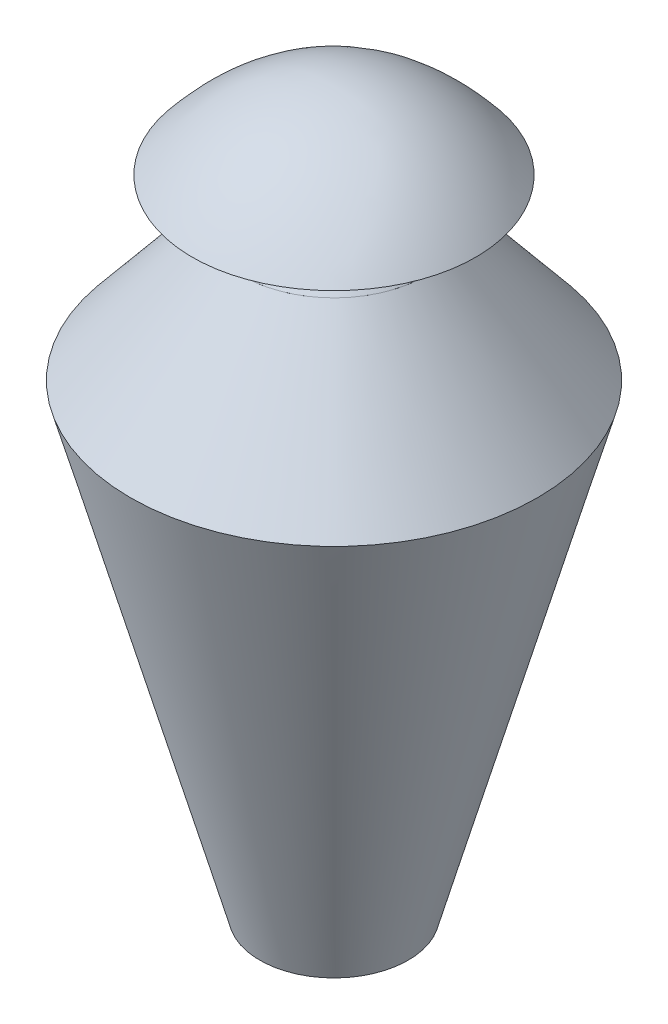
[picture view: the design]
ISO-10303-21;
HEADER;
FILE_DESCRIPTION(('STEP AP214'),'2;1');
FILE_NAME('part.step','',(''),(''),'','','');
FILE_SCHEMA(('AUTOMOTIVE_DESIGN { 1 0 10303 214 1 1 1 1 }'));
ENDSEC;
DATA;
#1=APPLICATION_CONTEXT('core data for automotive mechanical design processes');
#2=APPLICATION_PROTOCOL_DEFINITION('international standard','automotive_design',2000,#1);
#3=PRODUCT_CONTEXT('',#1,'mechanical');
#4=PRODUCT('Part','Part','',(#3));
#5=PRODUCT_RELATED_PRODUCT_CATEGORY('part','',(#4));
#6=PRODUCT_DEFINITION_FORMATION('','',#4);
#7=PRODUCT_DEFINITION_CONTEXT('part definition',#1,'design');
#8=PRODUCT_DEFINITION('design','',#6,#7);
#9=PRODUCT_DEFINITION_SHAPE('','',#8);
#10=(LENGTH_UNIT() NAMED_UNIT(*) SI_UNIT(.MILLI.,.METRE.));
#11=(NAMED_UNIT(*) PLANE_ANGLE_UNIT() SI_UNIT($,.RADIAN.));
#12=(NAMED_UNIT(*) SI_UNIT($,.STERADIAN.) SOLID_ANGLE_UNIT());
#13=UNCERTAINTY_MEASURE_WITH_UNIT(LENGTH_MEASURE(1.E-05),#10,'distance_accuracy_value','');
#14=(GEOMETRIC_REPRESENTATION_CONTEXT(3) GLOBAL_UNCERTAINTY_ASSIGNED_CONTEXT((#13)) GLOBAL_UNIT_ASSIGNED_CONTEXT((#10,
#11,#12)) REPRESENTATION_CONTEXT('',''));
#15=CARTESIAN_POINT('',(0.,0.,0.));
#16=DIRECTION('',(0.,0.,1.));
#17=DIRECTION('',(1.,0.,0.));
#18=AXIS2_PLACEMENT_3D('',#15,#16,#17);
#19=CARTESIAN_POINT('',(-14.2559215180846,82.6136920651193,-14.4318182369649));
#20=CARTESIAN_POINT('',(-8.55355290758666,89.3983986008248,-14.4318182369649));
#21=CARTESIAN_POINT('',(-2.85118429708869,93.0930925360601,-14.4318182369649));
#22=CARTESIAN_POINT('',(2.85118431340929,93.0720125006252,-14.4318182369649));
#23=CARTESIAN_POINT('',(8.55355292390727,89.3990041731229,-14.4318182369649));
#24=CARTESIAN_POINT('',(14.2559215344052,82.6614479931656,-14.4318182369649));
#25=CARTESIAN_POINT('',(-14.2559215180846,89.5757486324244,-8.65516518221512));
#26=CARTESIAN_POINT('',(-8.55355290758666,96.904811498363,-8.65516518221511));
#27=CARTESIAN_POINT('',(-2.85118429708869,100.30232000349,-8.65516518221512));
#28=CARTESIAN_POINT('',(2.85118431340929,100.275838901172,-8.65516518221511));
#29=CARTESIAN_POINT('',(8.55355292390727,96.8840880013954,-8.65516518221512));
#30=CARTESIAN_POINT('',(14.2559215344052,89.5838472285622,-8.65516518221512));
#31=CARTESIAN_POINT('',(-14.2559215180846,93.3592027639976,-2.87851212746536));
#32=CARTESIAN_POINT('',(-8.55355290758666,100.377822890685,-2.87851212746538));
#33=CARTESIAN_POINT('',(-2.85118429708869,103.246310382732,-2.87851212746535));
#34=CARTESIAN_POINT('',(2.85118431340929,103.179594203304,-2.87851212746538));
#35=CARTESIAN_POINT('',(8.55355292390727,100.331467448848,-2.87851212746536));
#36=CARTESIAN_POINT('',(14.2559215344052,93.3337100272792,-2.87851212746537));
#37=CARTESIAN_POINT('',(-14.2559215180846,93.3444529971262,2.89814092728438));
#38=CARTESIAN_POINT('',(-8.55355290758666,100.371031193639,2.89814092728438));
#39=CARTESIAN_POINT('',(-2.85118429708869,103.205456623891,2.89814092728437));
#40=CARTESIAN_POINT('',(2.85118431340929,103.258325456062,2.89814092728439));
#41=CARTESIAN_POINT('',(8.55355292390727,100.40060309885,2.89814092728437));
#42=CARTESIAN_POINT('',(14.2559215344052,93.3631287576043,2.89814092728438));
#43=CARTESIAN_POINT('',(-14.2559215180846,89.5573572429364,8.67479398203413));
#44=CARTESIAN_POINT('',(-8.55355290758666,96.8645126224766,8.67479398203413));
#45=CARTESIAN_POINT('',(-2.85118429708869,100.264019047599,8.67479398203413));
#46=CARTESIAN_POINT('',(2.85118431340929,100.301314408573,8.67479398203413));
#47=CARTESIAN_POINT('',(8.55355292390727,96.8903892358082,8.67479398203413));
#48=CARTESIAN_POINT('',(14.2559215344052,89.5657791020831,8.67479398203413));
#49=CARTESIAN_POINT('',(-14.2559215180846,82.6217733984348,14.4514470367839));
#50=CARTESIAN_POINT('',(-8.55355290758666,89.3882817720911,14.4514470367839));
#51=CARTESIAN_POINT('',(-2.85118429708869,93.0341993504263,14.4514470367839));
#52=CARTESIAN_POINT('',(2.85118431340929,93.0764137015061,14.4514470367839));
#53=CARTESIAN_POINT('',(8.55355292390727,89.3744885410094,14.4514470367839));
#54=CARTESIAN_POINT('',(14.2559215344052,82.5669419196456,14.4514470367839));
#55=B_SPLINE_SURFACE_WITH_KNOTS('',5,5,((#19,#20,#21,#22,#23,#24),(#25,#26,#27,#28,#29,#30),
(#31,#32,#33,#34,#35,#36),(#37,#38,#39,#40,#41,#42),(#43,#44,#45,#46,#47,#48),(#49,#50,#51,#52,
#53,#54)),.UNSPECIFIED.,.F.,.F.,.F.,(6,6),(6,6),(-13.7340018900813,15.1492633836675),
(-14.2559215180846,14.2559215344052),.UNSPECIFIED.);
#56=OFFSET_SURFACE('',#55,10.,.F.);
#57=CARTESIAN_POINT('',(0.000152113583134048,98.2263380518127,-21.67346671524));
#58=CARTESIAN_POINT('',(-0.354370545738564,98.2261840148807,-21.6736080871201));
#59=CARTESIAN_POINT('',(-0.708894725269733,98.2262117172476,-21.6648915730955));
#60=CARTESIAN_POINT('',(-1.41708255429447,98.2265999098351,-21.6298200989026));
#61=CARTESIAN_POINT('',(-1.77074617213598,98.2269604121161,-21.6034644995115));
#62=CARTESIAN_POINT('',(-2.47633651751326,98.2279835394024,-21.5331908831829));
#63=CARTESIAN_POINT('',(-2.82826318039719,98.228646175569,-21.4892722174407));
#64=CARTESIAN_POINT('',(-3.52951266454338,98.2302345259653,-21.3840080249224));
#65=CARTESIAN_POINT('',(-3.87883538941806,98.2311602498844,-21.3226618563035));
#66=CARTESIAN_POINT('',(-4.57401850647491,98.2332265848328,-21.1827248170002));
#67=CARTESIAN_POINT('',(-4.91987880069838,98.2343672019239,-21.1041334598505));
#68=CARTESIAN_POINT('',(-5.60728765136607,98.2368061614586,-20.9299397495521));
#69=CARTESIAN_POINT('',(-5.94883620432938,98.2381045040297,-20.8343373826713));
#70=CARTESIAN_POINT('',(-6.62678251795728,98.2407918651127,-20.6264084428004));
#71=CARTESIAN_POINT('',(-6.96318055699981,98.2421808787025,-20.514082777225));
#72=CARTESIAN_POINT('',(-7.62999662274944,98.2449802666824,-20.273043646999));
#73=CARTESIAN_POINT('',(-7.96041551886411,98.2463906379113,-20.144332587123));
#74=CARTESIAN_POINT('',(-8.61446529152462,98.2491797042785,-19.8708905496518));
#75=CARTESIAN_POINT('',(-8.93809773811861,98.2505584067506,-19.7261633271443));
#76=CARTESIAN_POINT('',(-9.57780759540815,98.2532322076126,-19.421091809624));
#77=CARTESIAN_POINT('',(-9.89388704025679,98.254527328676,-19.2607517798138));
#78=CARTESIAN_POINT('',(-10.5177613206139,98.2569855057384,-18.9248866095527));
#79=CARTESIAN_POINT('',(-10.8255583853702,98.2581485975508,-18.7493656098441));
#80=CARTESIAN_POINT('',(-11.4321706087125,98.2602998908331,-18.3835955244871));
#81=CARTESIAN_POINT('',(-11.7309879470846,98.2612881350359,-18.1933500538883));
#82=CARTESIAN_POINT('',(-12.31896906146,98.26305574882,-17.7986102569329));
#83=CARTESIAN_POINT('',(-12.6081348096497,98.2638351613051,-17.5941188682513));
#84=CARTESIAN_POINT('',(-13.1761594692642,98.2651639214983,-17.1713872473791));
#85=CARTESIAN_POINT('',(-13.4550201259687,98.2657133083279,-16.9531493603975));
#86=CARTESIAN_POINT('',(-14.001795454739,98.2665784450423,-16.5034429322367));
#87=CARTESIAN_POINT('',(-14.2697116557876,98.2668942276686,-16.2719762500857));
#88=CARTESIAN_POINT('',(-14.7940014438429,98.2672699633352,-15.7963633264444));
#89=CARTESIAN_POINT('',(-15.0503759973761,98.2673299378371,-15.5522181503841));
#90=CARTESIAN_POINT('',(-15.5510088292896,98.2671883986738,-15.0518067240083));
#91=CARTESIAN_POINT('',(-15.7952671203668,98.2669868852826,-14.7955404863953));
#92=CARTESIAN_POINT('',(-16.2711137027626,98.2663272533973,-14.2714596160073));
#93=CARTESIAN_POINT('',(-16.5027008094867,98.2658691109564,-14.0036439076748));
#94=CARTESIAN_POINT('',(-16.9526689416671,98.2647087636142,-13.4570563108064));
#95=CARTESIAN_POINT('',(-17.1710475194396,98.2640065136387,-13.1782824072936));
#96=CARTESIAN_POINT('',(-17.594078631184,98.2623758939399,-12.6103967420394));
#97=CARTESIAN_POINT('',(-17.7987276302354,98.2614474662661,-12.321282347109));
#98=CARTESIAN_POINT('',(-18.1937966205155,98.2593864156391,-11.7333656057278));
#99=CARTESIAN_POINT('',(-18.3842123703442,98.2582537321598,-11.4345604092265));
#100=CARTESIAN_POINT('',(-18.7503333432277,98.2558083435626,-10.8279463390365));
#101=CARTESIAN_POINT('',(-18.9260340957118,98.2544955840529,-10.5201347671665));
#102=CARTESIAN_POINT('',(-19.2622613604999,98.2517387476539,-9.89620298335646));
#103=CARTESIAN_POINT('',(-19.4227829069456,98.2502946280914,-9.58008009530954));
#104=CARTESIAN_POINT('',(-19.7282134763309,98.24732347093,-8.94026268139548));
#105=CARTESIAN_POINT('',(-19.8731177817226,98.2457964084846,-8.61656590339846));
#106=CARTESIAN_POINT('',(-20.1469027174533,98.2427117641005,-7.96238046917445));
#107=CARTESIAN_POINT('',(-20.2757797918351,98.2411541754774,-7.6318903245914));
#108=CARTESIAN_POINT('',(-20.5171332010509,98.2380678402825,-6.96493099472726));
#109=CARTESIAN_POINT('',(-20.629607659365,98.236539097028,-6.62846113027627));
#110=CARTESIAN_POINT('',(-20.8378199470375,98.2335767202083,-5.95037582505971));
#111=CARTESIAN_POINT('',(-20.9335575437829,98.2321430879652,-5.60876031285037));
#112=CARTESIAN_POINT('',(-21.1080076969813,98.2294401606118,-4.92122556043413));
#113=CARTESIAN_POINT('',(-21.1867210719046,98.2281708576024,-4.57530652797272));
#114=CARTESIAN_POINT('',(-21.326885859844,98.2258622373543,-3.88000656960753));
#115=CARTESIAN_POINT('',(-21.3883381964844,98.2248229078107,-3.53062582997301));
#116=CARTESIAN_POINT('',(-21.493799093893,98.2230217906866,-2.82926835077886));
#117=CARTESIAN_POINT('',(-21.5378090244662,98.2222599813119,-2.47729181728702));
#118=CARTESIAN_POINT('',(-21.6082515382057,98.221055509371,-1.77161733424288));
#119=CARTESIAN_POINT('',(-21.6346858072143,98.220612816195,-1.41791955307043));
#120=CARTESIAN_POINT('',(-21.6698956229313,98.2200773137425,-0.709670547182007));
#121=CARTESIAN_POINT('',(-21.6786724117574,98.2199844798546,-0.355119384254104));
#122=CARTESIAN_POINT('',(-21.67853948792,98.2201623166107,0.35397248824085));
#123=CARTESIAN_POINT('',(-21.6696301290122,98.2204329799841,0.708513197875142));
#124=CARTESIAN_POINT('',(-21.6341515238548,98.2213311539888,1.41672051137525));
#125=CARTESIAN_POINT('',(-21.6075817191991,98.2219586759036,1.77038708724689));
#126=CARTESIAN_POINT('',(-21.5368635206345,98.2235440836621,2.47597844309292));
#127=CARTESIAN_POINT('',(-21.4927140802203,98.2245019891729,2.82790311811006));
#128=CARTESIAN_POINT('',(-21.3869745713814,98.2267026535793,3.52913868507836));
#129=CARTESIAN_POINT('',(-21.325383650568,98.2279454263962,3.87844944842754));
#130=CARTESIAN_POINT('',(-21.1849394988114,98.2306681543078,4.57361194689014));
#131=CARTESIAN_POINT('',(-21.106084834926,98.2321481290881,4.91946339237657));
#132=CARTESIAN_POINT('',(-20.9313451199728,98.235281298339,5.60687030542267));
#133=CARTESIAN_POINT('',(-20.8354584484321,98.2369345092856,5.94842536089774));
#134=CARTESIAN_POINT('',(-20.6269454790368,98.2403388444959,6.62638864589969));
#135=CARTESIAN_POINT('',(-20.5143190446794,98.242089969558,6.96279683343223));
#136=CARTESIAN_POINT('',(-20.2726677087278,98.2456169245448,7.629619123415));
#137=CARTESIAN_POINT('',(-20.1436449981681,98.2473927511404,7.96003402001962));
#138=CARTESIAN_POINT('',(-19.8695848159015,98.2509037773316,8.61404510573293));
#139=CARTESIAN_POINT('',(-19.7245518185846,98.2526389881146,8.93764316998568));
#140=CARTESIAN_POINT('',(-19.4188869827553,98.2560131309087,9.57723702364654));
#141=CARTESIAN_POINT('',(-19.2582610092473,98.2576520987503,9.89323561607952));
#142=CARTESIAN_POINT('',(-18.9218502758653,98.2607806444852,10.5169052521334));
#143=CARTESIAN_POINT('',(-18.7460712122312,98.2622702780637,10.8245793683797));
#144=CARTESIAN_POINT('',(-18.3798214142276,98.2650512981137,11.4309072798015));
#145=CARTESIAN_POINT('',(-18.1893558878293,98.2663427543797,11.7295642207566));
#146=CARTESIAN_POINT('',(-17.7942237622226,98.2686974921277,12.3171752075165));
#147=CARTESIAN_POINT('',(-17.5895623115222,98.2697608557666,12.6061327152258));
#148=CARTESIAN_POINT('',(-17.1665427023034,98.2716368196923,13.1737035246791));
#149=CARTESIAN_POINT('',(-16.9481887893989,98.2724494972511,13.4523199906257));
#150=CARTESIAN_POINT('',(-16.4983007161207,98.2738071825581,13.9986027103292));
#151=CARTESIAN_POINT('',(-16.2667693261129,98.2743522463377,14.2662712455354));
#152=CARTESIAN_POINT('',(-15.7910569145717,98.2751622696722,14.790078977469));
#153=CARTESIAN_POINT('',(-15.5468769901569,98.2754272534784,15.0462191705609));
#154=CARTESIAN_POINT('',(-15.0464164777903,98.2756694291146,15.546409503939));
#155=CARTESIAN_POINT('',(-14.7901354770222,98.2756466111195,15.7904592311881));
#156=CARTESIAN_POINT('',(-14.2660453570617,98.2753134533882,16.265917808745));
#157=CARTESIAN_POINT('',(-13.9982347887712,98.275003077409,16.4973250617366));
#158=CARTESIAN_POINT('',(-13.4516730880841,98.2741060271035,16.9469650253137));
#159=CARTESIAN_POINT('',(-13.1729195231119,98.2735192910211,17.1651947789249));
#160=CARTESIAN_POINT('',(-12.6050793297,98.2720784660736,17.5879735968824));
#161=CARTESIAN_POINT('',(-12.3159892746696,98.2712242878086,17.7925180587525));
#162=CARTESIAN_POINT('',(-11.7281268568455,98.2692640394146,18.1874232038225));
#163=CARTESIAN_POINT('',(-11.4293510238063,98.2681578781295,18.3777787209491));
#164=CARTESIAN_POINT('',(-10.8228088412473,98.2657215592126,18.7438114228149));
#165=CARTESIAN_POINT('',(-10.5150396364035,98.2643913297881,18.9194838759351));
#166=CARTESIAN_POINT('',(-9.89123662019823,98.2615487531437,19.2556750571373));
#167=CARTESIAN_POINT('',(-9.57520081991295,98.2600363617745,19.4161900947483));
#168=CARTESIAN_POINT('',(-8.9356160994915,98.2568840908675,19.7216204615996));
#169=CARTESIAN_POINT('',(-8.61206597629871,98.2552441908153,19.8665332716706));
#170=CARTESIAN_POINT('',(-7.95821886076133,98.2518971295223,20.1403551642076));
#171=CARTESIAN_POINT('',(-7.62792109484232,98.2501899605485,20.2692623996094));
#172=CARTESIAN_POINT('',(-6.96136431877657,98.2467673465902,20.5107131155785));
#173=CARTESIAN_POINT('',(-6.62510479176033,98.2450519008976,20.6232551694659));
#174=CARTESIAN_POINT('',(-5.94744505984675,98.241692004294,20.8316350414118));
#175=CARTESIAN_POINT('',(-5.60604481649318,98.2400475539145,20.9274727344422));
#176=CARTESIAN_POINT('',(-4.91893425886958,98.236903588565,21.1021557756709));
#177=CARTESIAN_POINT('',(-4.57322407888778,98.235404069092,21.1810016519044));
#178=CARTESIAN_POINT('',(-3.87832896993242,98.2326154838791,21.3214654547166));
#179=CARTESIAN_POINT('',(-3.52914412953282,98.2313264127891,21.3830838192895));
#180=CARTESIAN_POINT('',(-2.82814224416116,98.2290115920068,21.4889086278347));
#181=CARTESIAN_POINT('',(-2.47632518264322,98.2279858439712,21.5331149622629));
#182=CARTESIAN_POINT('',(-1.77091157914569,98.2262377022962,21.6039808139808));
#183=CARTESIAN_POINT('',(-1.41731495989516,98.2255153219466,21.6306395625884));
#184=CARTESIAN_POINT('',(-0.709208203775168,98.2244026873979,21.666322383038));
#185=CARTESIAN_POINT('',(-0.35469800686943,98.2240124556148,21.675345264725));
#186=CARTESIAN_POINT('',(0.354352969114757,98.223586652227,21.6757127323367));
#187=CARTESIAN_POINT('',(0.708893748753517,98.223551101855,21.667056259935));
#188=CARTESIAN_POINT('',(1.41712089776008,98.2238083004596,21.6321032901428));
#189=CARTESIAN_POINT('',(1.7708072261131,98.2241010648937,21.6058059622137));
#190=CARTESIAN_POINT('',(2.47645270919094,98.2249838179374,21.5356547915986));
#191=CARTESIAN_POINT('',(2.82841177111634,98.2255738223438,21.4918000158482));
#192=CARTESIAN_POINT('',(3.52974086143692,98.2270110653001,21.3866652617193));
#193=CARTESIAN_POINT('',(3.87911071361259,98.2278583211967,21.32538410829));
#194=CARTESIAN_POINT('',(4.57440732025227,98.229760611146,21.1855769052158));
#195=CARTESIAN_POINT('',(4.92033382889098,98.2308156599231,21.1070496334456));
#196=CARTESIAN_POINT('',(5.60789618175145,98.2330749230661,20.9329813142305));
#197=CARTESIAN_POINT('',(5.94953181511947,98.2342791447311,20.8374394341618));
#198=CARTESIAN_POINT('',(6.62767001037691,98.2367726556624,20.6296240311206));
#199=CARTESIAN_POINT('',(6.96417263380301,98.2380619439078,20.5173507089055));
#200=CARTESIAN_POINT('',(7.63121365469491,98.240658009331,20.2764055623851));
#201=CARTESIAN_POINT('',(7.96175268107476,98.241964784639,20.1477354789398));
#202=CARTESIAN_POINT('',(8.61607286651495,98.2445494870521,19.8743509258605));
#203=CARTESIAN_POINT('',(8.93985496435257,98.2458274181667,19.7296387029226));
#204=CARTESIAN_POINT('',(9.5798887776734,98.2483060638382,19.4245675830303));
#205=CARTESIAN_POINT('',(9.89614186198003,98.2495067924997,19.2642115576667));
#206=CARTESIAN_POINT('',(10.5203614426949,98.2517865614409,18.9282913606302));
#207=CARTESIAN_POINT('',(10.8283300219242,98.2528656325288,18.7527310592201));
#208=CARTESIAN_POINT('',(11.4352508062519,98.2548672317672,18.3868715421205));
#209=CARTESIAN_POINT('',(11.7342058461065,98.2557898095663,18.1965770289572));
#210=CARTESIAN_POINT('',(12.3224047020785,98.2574546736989,17.8017396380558));
#211=CARTESIAN_POINT('',(12.6116518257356,98.258197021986,17.5972016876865));
#212=CARTESIAN_POINT('',(13.1797822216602,98.2594864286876,17.174380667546));
#213=CARTESIAN_POINT('',(13.4586686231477,98.2600335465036,16.9561018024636));
#214=CARTESIAN_POINT('',(14.0054694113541,98.2609213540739,16.5063094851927));
#215=CARTESIAN_POINT('',(14.2733858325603,98.2612620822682,16.2747985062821));
#216=CARTESIAN_POINT('',(14.7976575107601,98.2617212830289,15.7990821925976));
#217=CARTESIAN_POINT('',(15.0540137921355,98.2618397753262,15.5548779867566));
#218=CARTESIAN_POINT('',(15.5545909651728,98.2618480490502,15.0543345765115));
#219=CARTESIAN_POINT('',(15.7988118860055,98.2617378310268,14.7979954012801));
#220=CARTESIAN_POINT('',(16.2745686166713,98.2612893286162,14.2737539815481));
#221=CARTESIAN_POINT('',(16.50610306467,98.2609510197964,14.0058505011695));
#222=CARTESIAN_POINT('',(16.9559563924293,98.2600517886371,13.4590717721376));
#223=CARTESIAN_POINT('',(17.1742724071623,98.2594908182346,13.1801941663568));
#224=CARTESIAN_POINT('',(17.5971734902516,98.2581561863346,12.6120853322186));
#225=CARTESIAN_POINT('',(17.8017544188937,98.2573824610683,12.3228510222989));
#226=CARTESIAN_POINT('',(18.1966824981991,98.255638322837,11.7346809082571));
#227=CARTESIAN_POINT('',(18.3870248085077,98.2546678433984,11.4357418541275));
#228=CARTESIAN_POINT('',(18.7529866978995,98.2525538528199,10.828853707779));
#229=CARTESIAN_POINT('',(18.928601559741,98.2514102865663,10.5209017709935));
#230=CARTESIAN_POINT('',(19.2646451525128,98.2489935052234,9.89668893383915));
#231=CARTESIAN_POINT('',(19.4250688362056,98.2477202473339,9.58042531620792));
#232=CARTESIAN_POINT('',(19.7302948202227,98.2450916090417,8.94032104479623));
#233=CARTESIAN_POINT('',(19.8750920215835,98.2437362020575,8.6164779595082));
#234=CARTESIAN_POINT('',(20.1486512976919,98.2409941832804,7.9620022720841));
#235=CARTESIAN_POINT('',(20.2774097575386,98.2396075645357,7.6313681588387));
#236=CARTESIAN_POINT('',(20.518508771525,98.2368641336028,6.9641375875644));
#237=CARTESIAN_POINT('',(20.6308480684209,98.2355073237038,6.62754067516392));
#238=CARTESIAN_POINT('',(20.8387684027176,98.2328932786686,5.94923364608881));
#239=CARTESIAN_POINT('',(20.9343505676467,98.2316360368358,5.6075238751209));
#240=CARTESIAN_POINT('',(21.1084682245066,98.2292937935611,4.9198436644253));
#241=CARTESIAN_POINT('',(21.187006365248,98.2282087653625,4.57387389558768));
#242=CARTESIAN_POINT('',(21.3268090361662,98.2262734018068,3.87851261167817));
#243=CARTESIAN_POINT('',(21.3880760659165,98.2254230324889,3.5291215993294));
#244=CARTESIAN_POINT('',(21.4931634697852,98.224004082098,2.82776393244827));
#245=CARTESIAN_POINT('',(21.5369857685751,98.2234354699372,2.47579756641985));
#246=CARTESIAN_POINT('',(21.6070491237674,98.2226254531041,1.77016096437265));
#247=CARTESIAN_POINT('',(21.6332922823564,98.2223840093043,1.41649093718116));
#248=CARTESIAN_POINT('',(21.6681203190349,98.2222551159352,0.708313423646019));
#249=CARTESIAN_POINT('',(21.6767067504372,98.2223676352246,0.353806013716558));
#250=CARTESIAN_POINT('',(21.6761996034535,98.2229533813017,-0.355185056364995));
#251=CARTESIAN_POINT('',(21.6671065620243,98.2234265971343,-0.709668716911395));
#252=CARTESIAN_POINT('',(21.6312729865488,98.2247195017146,-1.41775171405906));
#253=CARTESIAN_POINT('',(21.6045319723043,98.2255391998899,-1.77135102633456));
#254=CARTESIAN_POINT('',(21.5334878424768,98.2274925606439,-2.47680153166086));
#255=CARTESIAN_POINT('',(21.4891836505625,98.2286262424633,-2.828652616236));
#256=CARTESIAN_POINT('',(21.3831494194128,98.2311629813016,-3.52973634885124));
#257=CARTESIAN_POINT('',(21.3214184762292,98.2325660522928,-3.87896886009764));
#258=CARTESIAN_POINT('',(21.1807153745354,98.2355898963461,-4.57395282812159));
#259=CARTESIAN_POINT('',(21.1017426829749,98.2372106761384,-4.91970417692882));
#260=CARTESIAN_POINT('',(20.9267971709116,98.240598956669,-5.60688747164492));
#261=CARTESIAN_POINT('',(20.8308238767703,98.2423664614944,-5.94831929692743));
#262=CARTESIAN_POINT('',(20.6221680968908,98.2459736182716,-6.62602347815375));
#263=CARTESIAN_POINT('',(20.5094862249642,98.2478132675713,-6.96229602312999));
#264=CARTESIAN_POINT('',(20.2677511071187,98.2514929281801,-7.62884907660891));
#265=CARTESIAN_POINT('',(20.1387001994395,98.2533329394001,-7.95913043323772));
#266=CARTESIAN_POINT('',(19.8646056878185,98.256949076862,-8.61288954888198));
#267=CARTESIAN_POINT('',(19.7195661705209,98.2587252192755,-8.93636902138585));
#268=CARTESIAN_POINT('',(19.4139077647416,98.2621577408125,-9.575745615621));
#269=CARTESIAN_POINT('',(19.2532942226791,98.2638141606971,-9.89164529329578));
#270=CARTESIAN_POINT('',(18.9169289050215,98.2669562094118,-10.5151290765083));
#271=CARTESIAN_POINT('',(18.7411827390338,98.2684419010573,-10.8227162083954));
#272=CARTESIAN_POINT('',(18.3750183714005,98.2711927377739,-11.4288854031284));
#273=CARTESIAN_POINT('',(18.1846052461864,98.2724579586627,-11.7274705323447));
#274=CARTESIAN_POINT('',(17.7895883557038,98.2747431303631,-12.3149585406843));
#275=CARTESIAN_POINT('',(17.5849893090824,98.2757631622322,-12.6038645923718));
#276=CARTESIAN_POINT('',(17.1621023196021,98.2775359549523,-13.1713529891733));
#277=CARTESIAN_POINT('',(16.943818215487,98.2782887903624,-13.4499381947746));
#278=CARTESIAN_POINT('',(16.494077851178,98.279509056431,-13.9961772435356));
#279=CARTESIAN_POINT('',(16.2626240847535,98.2799765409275,-14.2638331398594));
#280=CARTESIAN_POINT('',(15.7870761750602,98.2806131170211,-14.7876316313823));
#281=CARTESIAN_POINT('',(15.5429830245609,98.2807822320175,-15.0437751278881));
#282=CARTESIAN_POINT('',(15.0427047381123,98.2808160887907,-15.5439855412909));
#283=CARTESIAN_POINT('',(14.7865191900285,98.2806808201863,-15.7880520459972));
#284=CARTESIAN_POINT('',(14.2626236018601,98.2801105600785,-16.2635569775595));
#285=CARTESIAN_POINT('',(13.9949120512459,98.2796755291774,-16.4949937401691));
#286=CARTESIAN_POINT('',(13.4485550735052,98.2785267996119,-16.9446920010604));
#287=CARTESIAN_POINT('',(13.169907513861,98.2778130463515,-17.1629509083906));
#288=CARTESIAN_POINT('',(12.6023125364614,98.2761109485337,-17.5857747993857));
#289=CARTESIAN_POINT('',(12.3133628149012,98.2751225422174,-17.7903366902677));
#290=CARTESIAN_POINT('',(11.7258135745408,98.2728936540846,-18.1852642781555));
#291=CARTESIAN_POINT('',(11.4272116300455,98.2716531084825,-18.37562636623));
#292=CARTESIAN_POINT('',(10.8210276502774,98.2689584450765,-18.7416700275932));
#293=CARTESIAN_POINT('',(10.513443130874,98.2675042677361,-18.9173474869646));
#294=CARTESIAN_POINT('',(9.88999065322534,98.2644309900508,-19.2535588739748));
#295=CARTESIAN_POINT('',(9.57412031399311,98.2628118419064,-19.414088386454));
#296=CARTESIAN_POINT('',(8.93482448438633,98.2594654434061,-19.7195645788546));
#297=CARTESIAN_POINT('',(8.61139692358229,98.2577381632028,-19.8645069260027));
#298=CARTESIAN_POINT('',(7.95775157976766,98.2542368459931,-20.1383979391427));
#299=CARTESIAN_POINT('',(7.62753225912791,98.2524627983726,-20.2673429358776));
#300=CARTESIAN_POINT('',(6.96110726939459,98.2489309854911,-20.508862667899));
#301=CARTESIAN_POINT('',(6.62490077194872,98.2471732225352,-20.6214351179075));
#302=CARTESIAN_POINT('',(5.94732513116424,98.2437522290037,-20.8298658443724));
#303=CARTESIAN_POINT('',(5.6059557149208,98.2420890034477,-20.9257232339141));
#304=CARTESIAN_POINT('',(4.91888707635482,98.2389306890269,-21.1004323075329));
#305=CARTESIAN_POINT('',(4.57318780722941,98.2374356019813,-21.1792838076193));
#306=CARTESIAN_POINT('',(3.87830174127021,98.2346748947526,-21.319744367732));
#307=CARTESIAN_POINT('',(3.52911493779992,98.2334092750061,-21.3813533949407));
#308=CARTESIAN_POINT('',(2.82810509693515,98.2311556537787,-21.4871460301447));
#309=CARTESIAN_POINT('',(2.47628202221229,98.2301676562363,-21.5313293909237));
#310=CARTESIAN_POINT('',(1.77086035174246,98.2285061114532,-21.6021342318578));
#311=CARTESIAN_POINT('',(1.41726169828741,98.2278325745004,-21.6287551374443));
#312=CARTESIAN_POINT('',(0.709161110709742,98.2268247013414,-21.6643592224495));
#313=CARTESIAN_POINT('',(0.354659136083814,98.2264903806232,-21.6733415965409));
#314=CARTESIAN_POINT('',(0.000152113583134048,98.2263380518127,-21.67346671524));
#315=B_SPLINE_CURVE_WITH_KNOTS('',3,(#57,#58,#59,#60,#61,#62,#63,#64,#65,#66,#67,#68,#69,#70,
#71,#72,#73,#74,#75,#76,#77,#78,#79,#80,#81,#82,#83,#84,#85,#86,#87,#88,#89,#90,#91,#92,#93,#94,
#95,#96,#97,#98,#99,#100,#101,#102,#103,#104,#105,#106,#107,#108,#109,#110,#111,#112,#113,#114,
#115,#116,#117,#118,#119,#120,#121,#122,#123,#124,#125,#126,#127,#128,#129,#130,#131,#132,#133,
#134,#135,#136,#137,#138,#139,#140,#141,#142,#143,#144,#145,#146,#147,#148,#149,#150,#151,#152,
#153,#154,#155,#156,#157,#158,#159,#160,#161,#162,#163,#164,#165,#166,#167,#168,#169,#170,#171,
#172,#173,#174,#175,#176,#177,#178,#179,#180,#181,#182,#183,#184,#185,#186,#187,#188,#189,#190,
#191,#192,#193,#194,#195,#196,#197,#198,#199,#200,#201,#202,#203,#204,#205,#206,#207,#208,#209,
#210,#211,#212,#213,#214,#215,#216,#217,#218,#219,#220,#221,#222,#223,#224,#225,#226,#227,#228,
#229,#230,#231,#232,#233,#234,#235,#236,#237,#238,#239,#240,#241,#242,#243,#244,#245,#246,#247,
#248,#249,#250,#251,#252,#253,#254,#255,#256,#257,#258,#259,#260,#261,#262,#263,#264,#265,#266,
#267,#268,#269,#270,#271,#272,#273,#274,#275,#276,#277,#278,#279,#280,#281,#282,#283,#284,#285,
#286,#287,#288,#289,#290,#291,#292,#293,#294,#295,#296,#297,#298,#299,#300,#301,#302,#303,#304,
#305,#306,#307,#308,#309,#310,#311,#312,#313,#314),.UNSPECIFIED.,.F.,.F.,(4,2,2,2,2,2,2,2,2,2,2,
2,2,2,2,2,2,2,2,2,2,2,2,2,2,2,2,2,2,2,2,2,2,2,2,2,2,2,2,2,2,2,2,2,2,2,2,2,2,2,2,2,2,2,2,2,2,2,2,
2,2,2,2,2,2,2,2,2,2,2,2,2,2,2,2,2,2,2,2,2,2,2,2,2,2,2,2,2,2,2,2,2,2,2,2,2,2,2,2,2,2,2,2,2,2,2,2,
2,2,2,2,2,2,2,2,2,2,2,2,2,2,2,2,2,2,2,2,2,4),(0.,1.06345492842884,2.12694839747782,
3.190481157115,4.25405309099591,5.31765503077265,6.38125782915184,7.44480293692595,
8.50819213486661,9.57133254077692,10.6341833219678,11.6967451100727,12.7590468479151,
13.8211301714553,14.8830327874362,15.9447865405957,17.0064512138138,18.0681147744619,
19.1298774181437,20.1918362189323,21.2540673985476,22.3166138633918,23.379481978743,
24.442696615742,25.5062315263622,26.5700019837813,27.6338940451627,28.6978008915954,
29.7616565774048,30.825455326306,31.8891705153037,32.9527836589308,34.0163219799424,
35.0798390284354,36.1433897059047,37.2070037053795,38.2706696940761,39.3344240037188,
40.3982795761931,41.4621438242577,42.525866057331,43.5892917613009,44.6523190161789,
45.7149483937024,46.7772026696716,47.8390736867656,48.9006170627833,49.9619380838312,
51.0231672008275,52.0844325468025,53.1458316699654,54.2074680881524,55.2694597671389,
56.3318362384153,57.3945537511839,58.4575293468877,59.5206763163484,60.5839458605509,
61.647308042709,62.7106781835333,63.7740152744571,64.8373253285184,65.9006420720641,
66.9640053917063,68.0274404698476,69.0909392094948,70.1544880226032,71.2180933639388,
72.2817704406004,73.3455229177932,74.4093274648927,75.4731192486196,76.536798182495,
77.6003283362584,78.6636636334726,79.7267290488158,80.7894565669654,81.8518182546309,
82.9138564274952,83.9756967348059,85.0374427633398,86.09918623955,87.1610434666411,
88.2231300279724,89.2855352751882,90.3483000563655,91.4114039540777,92.4748598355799,
93.5386616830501,94.6027028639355,95.6668254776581,96.7308764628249,97.7947619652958,
98.8584934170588,99.9221074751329,100.985594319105,102.0489876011,103.112348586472,
104.175738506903,105.239193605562,106.302703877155,107.366247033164,108.429819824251,
109.493353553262,110.556735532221,111.619846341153,112.682593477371,113.744948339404,
114.806937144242,115.868574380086,116.929915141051,117.991055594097,119.052112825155,
120.113206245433,121.174439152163,122.235880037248,123.297559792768,124.359508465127,
125.421753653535,126.484307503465,127.547155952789,128.610247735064,129.673487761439,
130.736784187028,131.800092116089,132.863402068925,133.926727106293,134.990086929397,
136.053495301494),.UNSPECIFIED.);
#316=CARTESIAN_POINT('',(0.000152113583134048,98.2263380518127,-21.67346671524));
#317=VERTEX_POINT('',#316);
#318=EDGE_CURVE('E11',#317,#317,#315,.F.);
#319=ORIENTED_EDGE('',*,*,#318,.F.);
#320=EDGE_LOOP('',(#319));
#321=FACE_BOUND('',#320,.T.);
#322=ADVANCED_FACE('F44',(#321),#56,.T.);
#323=OPEN_SHELL('',(#322));
#324=SHELL_BASED_SURFACE_MODEL('B2',(#323));
#325=CARTESIAN_POINT('',(6.61785085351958,0.,0.));
#326=DIRECTION('',(0.,-1.,0.));
#327=DIRECTION('',(0.,0.,-1.));
#328=AXIS2_PLACEMENT_3D('',#325,#326,#327);
#329=PLANE('',#328);
#330=CARTESIAN_POINT('',(0.,0.,0.));
#331=DIRECTION('',(0.,-1.,0.));
#332=DIRECTION('',(0.,0.,-1.));
#333=AXIS2_PLACEMENT_3D('',#330,#331,#332);
#334=CIRCLE('',#333,11.3512260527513);
#335=CARTESIAN_POINT('',(0.,0.,-11.3512260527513));
#336=VERTEX_POINT('',#335);
#337=EDGE_CURVE('E99',#336,#336,#334,.T.);
#338=ORIENTED_EDGE('',*,*,#337,.T.);
#339=EDGE_LOOP('',(#338));
#340=FACE_BOUND('',#339,.T.);
#341=CARTESIAN_POINT('',(0.,0.,0.));
#342=DIRECTION('',(0.,-1.,0.));
#343=DIRECTION('',(0.,0.,-1.));
#344=AXIS2_PLACEMENT_3D('',#341,#342,#343);
#345=CIRCLE('',#344,6.61785085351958);
#346=CARTESIAN_POINT('',(0.,0.,-6.61785085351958));
#347=VERTEX_POINT('',#346);
#348=EDGE_CURVE('E43',#347,#347,#345,.T.);
#349=ORIENTED_EDGE('',*,*,#348,.F.);
#350=EDGE_LOOP('',(#349));
#351=FACE_BOUND('',#350,.T.);
#352=ADVANCED_FACE('F85',(#340,#351),#329,.T.);
#353=CARTESIAN_POINT('',(0.,91.8668136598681,0.));
#354=DIRECTION('',(0.,1.,0.));
#355=DIRECTION('',(0.,0.,1.));
#356=AXIS2_PLACEMENT_3D('',#353,#354,#355);
#357=CONICAL_SURFACE('',#356,13.9563269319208,0.0797124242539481);
#358=ORIENTED_EDGE('',*,*,#348,.T.);
#359=EDGE_LOOP('',(#358));
#360=FACE_BOUND('',#359,.T.);
#361=CARTESIAN_POINT('',(0.,91.8668136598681,0.));
#362=DIRECTION('',(0.,-1.,0.));
#363=DIRECTION('',(0.,0.,-1.));
#364=AXIS2_PLACEMENT_3D('',#361,#362,#363);
#365=CIRCLE('',#364,13.9563269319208);
#366=CARTESIAN_POINT('',(0.,91.8668136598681,-13.9563269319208));
#367=VERTEX_POINT('',#366);
#368=EDGE_CURVE('E91',#367,#367,#365,.T.);
#369=ORIENTED_EDGE('',*,*,#368,.F.);
#370=EDGE_LOOP('',(#369));
#371=FACE_BOUND('',#370,.T.);
#372=ADVANCED_FACE('F115',(#360,#371),#357,.F.);
#373=CARTESIAN_POINT('',(0.,71.0777751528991,0.));
#374=DIRECTION('',(0.,-1.,0.));
#375=DIRECTION('',(0.,0.,-1.));
#376=AXIS2_PLACEMENT_3D('',#373,#374,#375);
#377=CONICAL_SURFACE('',#376,31.0880345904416,0.68924885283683);
#378=ORIENTED_EDGE('',*,*,#368,.T.);
#379=EDGE_LOOP('',(#378));
#380=FACE_BOUND('',#379,.T.);
#381=CARTESIAN_POINT('',(0.,71.0777751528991,0.));
#382=DIRECTION('',(0.,-1.,0.));
#383=DIRECTION('',(0.,0.,-1.));
#384=AXIS2_PLACEMENT_3D('',#381,#382,#383);
#385=CIRCLE('',#384,31.0880345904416);
#386=CARTESIAN_POINT('',(0.,71.0777751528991,-31.0880345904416));
#387=VERTEX_POINT('',#386);
#388=EDGE_CURVE('E95',#387,#387,#385,.T.);
#389=ORIENTED_EDGE('',*,*,#388,.F.);
#390=EDGE_LOOP('',(#389));
#391=FACE_BOUND('',#390,.T.);
#392=ADVANCED_FACE('F109',(#380,#391),#377,.T.);
#393=CARTESIAN_POINT('',(0.,0.,0.));
#394=DIRECTION('',(0.,1.,0.));
#395=DIRECTION('',(0.,0.,1.));
#396=AXIS2_PLACEMENT_3D('',#393,#394,#395);
#397=CONICAL_SURFACE('',#396,11.3512260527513,0.27085518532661);
#398=ORIENTED_EDGE('',*,*,#388,.T.);
#399=EDGE_LOOP('',(#398));
#400=FACE_BOUND('',#399,.T.);
#401=ORIENTED_EDGE('',*,*,#337,.F.);
#402=EDGE_LOOP('',(#401));
#403=FACE_BOUND('',#402,.T.);
#404=ADVANCED_FACE('F107',(#400,#403),#397,.T.);
#405=CLOSED_SHELL('',(#352,#372,#392,#404));
#406=MANIFOLD_SOLID_BREP('B6',#405);
#407=CARTESIAN_POINT('',(-14.2559215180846,82.6136920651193,-14.4318182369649));
#408=CARTESIAN_POINT('',(-8.55355290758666,89.3983986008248,-14.4318182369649));
#409=CARTESIAN_POINT('',(-2.85118429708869,93.0930925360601,-14.4318182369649));
#410=CARTESIAN_POINT('',(2.85118431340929,93.0720125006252,-14.4318182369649));
#411=CARTESIAN_POINT('',(8.55355292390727,89.3990041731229,-14.4318182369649));
#412=CARTESIAN_POINT('',(14.2559215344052,82.6614479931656,-14.4318182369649));
#413=CARTESIAN_POINT('',(-14.2559215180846,89.5757486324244,-8.65516518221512));
#414=CARTESIAN_POINT('',(-8.55355290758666,96.904811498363,-8.65516518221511));
#415=CARTESIAN_POINT('',(-2.85118429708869,100.30232000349,-8.65516518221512));
#416=CARTESIAN_POINT('',(2.85118431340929,100.275838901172,-8.65516518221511));
#417=CARTESIAN_POINT('',(8.55355292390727,96.8840880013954,-8.65516518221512));
#418=CARTESIAN_POINT('',(14.2559215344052,89.5838472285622,-8.65516518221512));
#419=CARTESIAN_POINT('',(-14.2559215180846,93.3592027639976,-2.87851212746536));
#420=CARTESIAN_POINT('',(-8.55355290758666,100.377822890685,-2.87851212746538));
#421=CARTESIAN_POINT('',(-2.85118429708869,103.246310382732,-2.87851212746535));
#422=CARTESIAN_POINT('',(2.85118431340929,103.179594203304,-2.87851212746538));
#423=CARTESIAN_POINT('',(8.55355292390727,100.331467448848,-2.87851212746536));
#424=CARTESIAN_POINT('',(14.2559215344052,93.3337100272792,-2.87851212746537));
#425=CARTESIAN_POINT('',(-14.2559215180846,93.3444529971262,2.89814092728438));
#426=CARTESIAN_POINT('',(-8.55355290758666,100.371031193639,2.89814092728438));
#427=CARTESIAN_POINT('',(-2.85118429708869,103.205456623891,2.89814092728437));
#428=CARTESIAN_POINT('',(2.85118431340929,103.258325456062,2.89814092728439));
#429=CARTESIAN_POINT('',(8.55355292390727,100.40060309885,2.89814092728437));
#430=CARTESIAN_POINT('',(14.2559215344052,93.3631287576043,2.89814092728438));
#431=CARTESIAN_POINT('',(-14.2559215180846,89.5573572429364,8.67479398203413));
#432=CARTESIAN_POINT('',(-8.55355290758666,96.8645126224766,8.67479398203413));
#433=CARTESIAN_POINT('',(-2.85118429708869,100.264019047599,8.67479398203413));
#434=CARTESIAN_POINT('',(2.85118431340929,100.301314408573,8.67479398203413));
#435=CARTESIAN_POINT('',(8.55355292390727,96.8903892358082,8.67479398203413));
#436=CARTESIAN_POINT('',(14.2559215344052,89.5657791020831,8.67479398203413));
#437=CARTESIAN_POINT('',(-14.2559215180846,82.6217733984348,14.4514470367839));
#438=CARTESIAN_POINT('',(-8.55355290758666,89.3882817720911,14.4514470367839));
#439=CARTESIAN_POINT('',(-2.85118429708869,93.0341993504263,14.4514470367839));
#440=CARTESIAN_POINT('',(2.85118431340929,93.0764137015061,14.4514470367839));
#441=CARTESIAN_POINT('',(8.55355292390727,89.3744885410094,14.4514470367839));
#442=CARTESIAN_POINT('',(14.2559215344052,82.5669419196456,14.4514470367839));
#443=B_SPLINE_SURFACE_WITH_KNOTS('',5,5,((#407,#408,#409,#410,#411,#412),(#413,#414,#415,#416,
#417,#418),(#419,#420,#421,#422,#423,#424),(#425,#426,#427,#428,#429,#430),(#431,#432,#433,#434,
#435,#436),(#437,#438,#439,#440,#441,#442)),.UNSPECIFIED.,.F.,.F.,.F.,(6,6),(6,6),
(-13.7340018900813,15.1492633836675),(-14.2559215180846,14.2559215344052),.UNSPECIFIED.);
#444=CARTESIAN_POINT('',(0.,91.8666404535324,-13.9563269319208));
#445=CARTESIAN_POINT('',(-0.228357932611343,91.8666473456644,-13.9563303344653));
#446=CARTESIAN_POINT('',(-0.456715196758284,91.8666629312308,-13.950717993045));
#447=CARTESIAN_POINT('',(-0.912875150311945,91.8667036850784,-13.9283004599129));
#448=CARTESIAN_POINT('',(-1.14067785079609,91.8667288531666,-13.9114954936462));
#449=CARTESIAN_POINT('',(-1.59517951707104,91.866780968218,-13.8667318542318));
#450=CARTESIAN_POINT('',(-1.82187850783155,91.8668079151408,-13.8387734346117));
#451=CARTESIAN_POINT('',(-2.27362967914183,91.8668618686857,-13.7717694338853));
#452=CARTESIAN_POINT('',(-2.49868187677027,91.8668888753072,-13.7327239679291));
#453=CARTESIAN_POINT('',(-2.9466011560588,91.8669414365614,-13.6436360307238));
#454=CARTESIAN_POINT('',(-3.16946821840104,91.8669669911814,-13.5935934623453));
#455=CARTESIAN_POINT('',(-3.61248304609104,91.8670139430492,-13.4826292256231));
#456=CARTESIAN_POINT('',(-3.83263074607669,91.8670353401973,-13.4217072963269));
#457=CARTESIAN_POINT('',(-4.26967615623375,91.8670674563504,-13.2891328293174));
#458=CARTESIAN_POINT('',(-4.48657379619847,91.867078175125,-13.2174800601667));
#459=CARTESIAN_POINT('',(-4.91659064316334,91.8670815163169,-13.063622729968));
#460=CARTESIAN_POINT('',(-5.12970989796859,91.8670741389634,-12.9814183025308));
#461=CARTESIAN_POINT('',(-5.55164847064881,91.8670468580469,-12.8066545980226));
#462=CARTESIAN_POINT('',(-5.76046798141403,91.8670269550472,-12.7140957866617));
#463=CARTESIAN_POINT('',(-6.17330513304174,91.8669782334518,-12.5188460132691));
#464=CARTESIAN_POINT('',(-6.37732296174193,91.8669494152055,-12.4161554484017));
#465=CARTESIAN_POINT('',(-6.78007193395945,91.8668855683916,-12.2008884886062));
#466=CARTESIAN_POINT('',(-6.97880313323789,91.8668505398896,-12.0883121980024));
#467=CARTESIAN_POINT('',(-7.37050805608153,91.8667762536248,-11.8535435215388));
#468=CARTESIAN_POINT('',(-7.56348165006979,91.8667369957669,-11.7313509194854));
#469=CARTESIAN_POINT('',(-7.94321138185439,91.8666573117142,-11.4776422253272));
#470=CARTESIAN_POINT('',(-8.12996725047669,91.866616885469,-11.3461257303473));
#471=CARTESIAN_POINT('',(-8.49680908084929,91.8665421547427,-11.074084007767));
#472=CARTESIAN_POINT('',(-8.67689479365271,91.8665078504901,-10.933558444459));
#473=CARTESIAN_POINT('',(-9.02995018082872,91.8664598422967,-10.6438345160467));
#474=CARTESIAN_POINT('',(-9.20291983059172,91.8664461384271,-10.4946361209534));
#475=CARTESIAN_POINT('',(-9.54132785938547,91.8664319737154,-10.1879356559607));
#476=CARTESIAN_POINT('',(-9.70676637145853,91.8664315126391,-10.0304337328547));
#477=CARTESIAN_POINT('',(-10.0297149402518,91.8664425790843,-9.70750738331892));
#478=CARTESIAN_POINT('',(-10.1872251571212,91.8664541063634,-9.54208311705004));
#479=CARTESIAN_POINT('',(-10.49393879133,91.8664894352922,-9.20370827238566));
#480=CARTESIAN_POINT('',(-10.6431422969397,91.8665132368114,-9.03075777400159));
#481=CARTESIAN_POINT('',(-10.93288389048,91.8665726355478,-8.67774295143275));
#482=CARTESIAN_POINT('',(-11.0734219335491,91.866608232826,-8.49767859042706));
#483=CARTESIAN_POINT('',(-11.3454947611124,91.8666879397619,-8.13086646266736));
#484=CARTESIAN_POINT('',(-11.4770293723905,91.8667320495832,-7.94411856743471));
#485=CARTESIAN_POINT('',(-11.730778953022,91.8668219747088,-7.56438917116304));
#486=CARTESIAN_POINT('',(-11.8529937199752,91.8668677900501,-7.37140753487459));
#487=CARTESIAN_POINT('',(-12.0878122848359,91.8669494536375,-6.97967869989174));
#488=CARTESIAN_POINT('',(-12.2004159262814,91.8669853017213,-6.7809314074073));
#489=CARTESIAN_POINT('',(-12.4157394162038,91.8670491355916,-6.37813946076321));
#490=CARTESIAN_POINT('',(-12.5184587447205,91.8670771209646,-6.1740945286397));
#491=CARTESIAN_POINT('',(-12.7137653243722,91.8671218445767,-5.76119628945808));
#492=CARTESIAN_POINT('',(-12.8063519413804,91.8671385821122,-5.55234268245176));
#493=CARTESIAN_POINT('',(-12.9811676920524,91.8671563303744,-5.13033680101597));
#494=CARTESIAN_POINT('',(-13.0633964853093,91.8671573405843,-4.91718438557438));
#495=CARTESIAN_POINT('',(-13.2172953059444,91.8671423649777,-4.48710468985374));
#496=CARTESIAN_POINT('',(-13.2889654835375,91.867126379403,-4.27017746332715));
#497=CARTESIAN_POINT('',(-13.4215716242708,91.86708088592,-3.83307951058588));
#498=CARTESIAN_POINT('',(-13.4825081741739,91.8670513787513,-3.6129089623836));
#499=CARTESIAN_POINT('',(-13.5934992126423,91.8669862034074,-3.16985668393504));
#500=CARTESIAN_POINT('',(-13.6435543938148,91.8669505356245,-2.94697512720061));
#501=CARTESIAN_POINT('',(-13.7326632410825,91.8668816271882,-2.49903015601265));
#502=CARTESIAN_POINT('',(-13.7717172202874,91.8668483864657,-2.27396680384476));
#503=CARTESIAN_POINT('',(-13.8387349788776,91.8667844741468,-1.8222021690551));
#504=CARTESIAN_POINT('',(-13.8666991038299,91.8667538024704,-1.59550093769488));
#505=CARTESIAN_POINT('',(-13.9114716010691,91.8666989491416,-1.14100930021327));
#506=CARTESIAN_POINT('',(-13.9282804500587,91.866674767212,-0.913218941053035));
#507=CARTESIAN_POINT('',(-13.9507019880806,91.8666384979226,-0.457093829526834));
#508=CARTESIAN_POINT('',(-13.9563149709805,91.8666264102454,-0.228759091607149));
#509=CARTESIAN_POINT('',(-13.9563307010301,91.8666177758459,0.227911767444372));
#510=CARTESIAN_POINT('',(-13.9507333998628,91.8666212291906,0.456247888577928));
#511=CARTESIAN_POINT('',(-13.9283414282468,91.8666432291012,0.912378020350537));
#512=CARTESIAN_POINT('',(-13.9115463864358,91.8666617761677,1.14017201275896));
#513=CARTESIAN_POINT('',(-13.8667990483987,91.8667098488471,1.59467150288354));
#514=CARTESIAN_POINT('',(-13.8388462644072,91.8667393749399,1.82137695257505));
#515=CARTESIAN_POINT('',(-13.7718524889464,91.8668014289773,2.27314988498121));
#516=CARTESIAN_POINT('',(-13.732811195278,91.8668339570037,2.49821732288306));
#517=CARTESIAN_POINT('',(-13.6437268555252,91.8669018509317,2.94618148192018));
#518=CARTESIAN_POINT('',(-13.593683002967,91.8669372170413,3.16907804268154));
#519=CARTESIAN_POINT('',(-13.482708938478,91.867005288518,3.61217189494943));
#520=CARTESIAN_POINT('',(-13.4217774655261,91.8670379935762,3.83236887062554));
#521=CARTESIAN_POINT('',(-13.2891771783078,91.8670911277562,4.26952449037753));
#522=CARTESIAN_POINT('',(-13.2175075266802,91.8671115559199,4.48648288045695));
#523=CARTESIAN_POINT('',(-13.063608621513,91.8671346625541,4.91662110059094));
#524=CARTESIAN_POINT('',(-12.9813793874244,91.8671373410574,5.12980093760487));
#525=CARTESIAN_POINT('',(-12.8065650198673,91.8671253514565,5.55185124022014));
#526=CARTESIAN_POINT('',(-12.7139807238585,91.8671106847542,5.76072205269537));
#527=CARTESIAN_POINT('',(-12.5186820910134,91.867069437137,6.17364321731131));
#528=CARTESIAN_POINT('',(-12.4159689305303,91.8670428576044,6.37769412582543));
#529=CARTESIAN_POINT('',(-12.2006591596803,91.8669807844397,6.78049475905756));
#530=CARTESIAN_POINT('',(-12.0880632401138,91.8669452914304,6.97924485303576));
#531=CARTESIAN_POINT('',(-11.8532600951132,91.8668655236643,7.37097677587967));
#532=CARTESIAN_POINT('',(-11.7310531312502,91.8668212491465,7.56395876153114));
#533=CARTESIAN_POINT('',(-11.4773232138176,91.8667330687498,7.94368595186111));
#534=CARTESIAN_POINT('',(-11.3458006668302,91.8666891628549,8.13043142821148));
#535=CARTESIAN_POINT('',(-11.0737552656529,91.8666095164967,8.49723802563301));
#536=CARTESIAN_POINT('',(-10.9332327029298,91.8665737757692,8.67729936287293));
#537=CARTESIAN_POINT('',(-10.6435224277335,91.8665160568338,9.03030967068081));
#538=CARTESIAN_POINT('',(-10.4943347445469,91.8664940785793,9.20325866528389));
#539=CARTESIAN_POINT('',(-10.1876499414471,91.8664660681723,9.54163370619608));
#540=CARTESIAN_POINT('',(-10.0301525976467,91.8664600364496,9.70705954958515));
#541=CARTESIAN_POINT('',(-9.70722557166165,91.8664633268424,10.0299928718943));
#542=CARTESIAN_POINT('',(-9.54179554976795,91.866472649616,10.187500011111));
#543=CARTESIAN_POINT('',(-9.20340214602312,91.866505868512,10.494213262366));
#544=CARTESIAN_POINT('',(-9.0304385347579,91.8665297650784,10.6434191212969));
#545=CARTESIAN_POINT('',(-8.67739039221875,91.86659322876,10.9331669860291));
#546=CARTESIAN_POINT('',(-8.4973056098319,91.8666327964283,11.0737086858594));
#547=CARTESIAN_POINT('',(-8.1304419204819,91.8667197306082,11.3457954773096));
#548=CARTESIAN_POINT('',(-7.94366250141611,91.8667670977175,11.477339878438));
#549=CARTESIAN_POINT('',(-7.56386199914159,91.8668596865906,11.7311135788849));
#550=CARTESIAN_POINT('',(-7.37084051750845,91.8669049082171,11.8533422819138));
#551=CARTESIAN_POINT('',(-6.97902977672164,91.866985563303,12.0881832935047));
#552=CARTESIAN_POINT('',(-6.78024043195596,91.8670209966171,12.2007954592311));
#553=CARTESIAN_POINT('',(-6.37738319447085,91.8670785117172,12.416124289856));
#554=CARTESIAN_POINT('',(-6.17331551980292,91.8671005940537,12.518841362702));
#555=CARTESIAN_POINT('',(-5.76039997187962,91.8671313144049,12.7141279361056));
#556=CARTESIAN_POINT('',(-5.55155246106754,91.8671399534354,12.8066982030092));
#557=CARTESIAN_POINT('',(-5.12957879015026,91.8671430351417,12.9814715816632));
#558=CARTESIAN_POINT('',(-4.91645289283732,91.8671374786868,13.0636753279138));
#559=CARTESIAN_POINT('',(-4.4864307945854,91.8671069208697,13.2175279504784));
#560=CARTESIAN_POINT('',(-4.26953468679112,91.8670819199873,13.2891770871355));
#561=CARTESIAN_POINT('',(-3.83249772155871,91.8670224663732,13.421742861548));
#562=CARTESIAN_POINT('',(-3.61235701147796,91.8669880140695,13.4826599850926));
#563=CARTESIAN_POINT('',(-3.16936040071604,91.8669172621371,13.5936152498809));
#564=CARTESIAN_POINT('',(-2.94650461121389,91.8668809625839,13.6436538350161));
#565=CARTESIAN_POINT('',(-2.49860893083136,91.8668117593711,13.732735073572));
#566=CARTESIAN_POINT('',(-2.2735690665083,91.8667788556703,13.7717778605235));
#567=CARTESIAN_POINT('',(-1.82184015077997,91.8667192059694,13.8387776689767));
#568=CARTESIAN_POINT('',(-1.59515106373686,91.8666924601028,13.8667344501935));
#569=CARTESIAN_POINT('',(-1.14066464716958,91.8666472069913,13.9114967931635));
#570=CARTESIAN_POINT('',(-0.912867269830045,91.866628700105,13.9283018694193));
#571=CARTESIAN_POINT('',(-0.456713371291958,91.8666044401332,13.9507171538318));
#572=CARTESIAN_POINT('',(-0.228356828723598,91.8665986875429,13.9563269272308));
#573=CARTESIAN_POINT('',(0.228356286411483,91.8666118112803,13.9563269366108));
#574=CARTESIAN_POINT('',(0.456712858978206,91.8666306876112,13.9507171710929));
#575=CARTESIAN_POINT('',(0.912866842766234,91.8666784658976,13.9283018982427));
#576=CARTESIAN_POINT('',(1.14066427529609,91.8667073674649,13.9114968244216));
#577=CARTESIAN_POINT('',(1.59515078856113,91.866768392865,13.8667344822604));
#578=CARTESIAN_POINT('',(1.82183991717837,91.8668005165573,13.838777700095));
#579=CARTESIAN_POINT('',(2.27356888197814,91.8668644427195,13.7717778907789));
#580=CARTESIAN_POINT('',(2.49860875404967,91.8668962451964,13.7327351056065));
#581=CARTESIAN_POINT('',(2.94650441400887,91.866956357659,13.6436538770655));
#582=CARTESIAN_POINT('',(3.16936017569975,91.866984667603,13.5936153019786));
#583=CARTESIAN_POINT('',(3.61235671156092,91.8670332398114,13.4826600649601));
#584=CARTESIAN_POINT('',(3.83249737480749,91.867053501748,13.421742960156));
#585=CARTESIAN_POINT('',(4.26953426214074,91.8670800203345,13.2891772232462));
#586=CARTESIAN_POINT('',(4.48643033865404,91.8670862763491,13.2175281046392));
#587=CARTESIAN_POINT('',(4.916452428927,91.867077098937,13.0636755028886));
#588=CARTESIAN_POINT('',(5.1295783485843,91.8670616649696,12.9814717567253));
#589=CARTESIAN_POINT('',(5.55155208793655,91.8670169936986,12.8066983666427));
#590=CARTESIAN_POINT('',(5.76039964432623,91.866987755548,12.7141280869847));
#591=CARTESIAN_POINT('',(6.17331526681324,91.866918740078,12.5188414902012));
#592=CARTESIAN_POINT('',(6.37738297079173,91.8668789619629,12.4161244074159));
#593=CARTESIAN_POINT('',(6.78024023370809,91.8667909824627,12.2007955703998));
#594=CARTESIAN_POINT('',(6.97902957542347,91.8667427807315,12.0881834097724));
#595=CARTESIAN_POINT('',(7.37084027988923,91.8666428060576,11.8533424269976));
#596=CARTESIAN_POINT('',(7.56386172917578,91.8665910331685,11.7311137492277));
#597=CARTESIAN_POINT('',(7.94366215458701,91.8664920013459,11.4773401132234));
#598=CARTESIAN_POINT('',(8.13044152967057,91.8664447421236,11.3457957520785));
#599=CARTESIAN_POINT('',(8.49730514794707,91.8663643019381,11.0737090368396));
#600=CARTESIAN_POINT('',(8.67738990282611,91.866331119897,10.9331673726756));
#601=CARTESIAN_POINT('',(9.03043803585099,91.8662856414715,10.6434195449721));
#602=CARTESIAN_POINT('',(9.20340166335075,91.8662733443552,10.4942136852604));
#603=CARTESIAN_POINT('',(9.54179512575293,91.8662669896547,10.1875004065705));
#604=CARTESIAN_POINT('',(9.7072251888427,91.8662729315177,10.0299932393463));
#605=CARTESIAN_POINT('',(10.0301522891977,91.8663021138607,9.70705986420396));
#606=CARTESIAN_POINT('',(10.1876496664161,91.8663253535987,9.54163399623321));
#607=CARTESIAN_POINT('',(10.4943345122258,91.8663880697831,9.20325892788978));
#608=CARTESIAN_POINT('',(10.6435222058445,91.8664275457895,9.03030993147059));
#609=CARTESIAN_POINT('',(10.9332324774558,91.8665191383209,8.67729964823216));
#610=CARTESIAN_POINT('',(11.0737550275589,91.8665712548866,8.49723833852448));
#611=CARTESIAN_POINT('',(11.3458003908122,91.8666814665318,8.13043181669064));
#612=CARTESIAN_POINT('',(11.4773229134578,91.8667395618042,7.94368638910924));
#613=CARTESIAN_POINT('',(11.7310527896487,91.8668532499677,7.56395929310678));
#614=CARTESIAN_POINT('',(11.8532597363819,91.8669088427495,7.37097735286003));
#615=CARTESIAN_POINT('',(12.0880628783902,91.8670080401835,6.97924547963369));
#616=CARTESIAN_POINT('',(12.2006588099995,91.8670516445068,6.78049538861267));
#617=CARTESIAN_POINT('',(12.4159686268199,91.8671267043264,6.37769472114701));
#618=CARTESIAN_POINT('',(12.5186818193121,91.8671581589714,6.17364377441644));
#619=CARTESIAN_POINT('',(12.7139805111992,91.8672060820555,5.76072253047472));
#620=CARTESIAN_POINT('',(12.8065648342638,91.8672225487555,5.55185167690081));
#621=CARTESIAN_POINT('',(12.9813792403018,91.8672353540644,5.12980131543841));
#622=CARTESIAN_POINT('',(13.0636084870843,91.8672316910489,4.9166214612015));
#623=CARTESIAN_POINT('',(13.2175074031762,91.8672042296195,4.48648324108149));
#624=CARTESIAN_POINT('',(13.2891770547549,91.8671804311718,4.26952486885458));
#625=CARTESIAN_POINT('',(13.4217773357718,91.8671186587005,3.83236931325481));
#626=CARTESIAN_POINT('',(13.4827088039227,91.8670806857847,3.61217238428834));
#627=CARTESIAN_POINT('',(13.5936828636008,91.8670007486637,3.16907862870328));
#628=CARTESIAN_POINT('',(13.6437267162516,91.8669587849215,2.94618211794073));
#629=CARTESIAN_POINT('',(13.732811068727,91.866877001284,2.49821801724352));
#630=CARTESIAN_POINT('',(13.7718523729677,91.8668371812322,2.27315058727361));
#631=CARTESIAN_POINT('',(13.8388461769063,91.8667605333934,1.82137761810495));
#632=CARTESIAN_POINT('',(13.8667989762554,91.8667237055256,1.59467212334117));
#633=CARTESIAN_POINT('',(13.9115463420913,91.8666617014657,1.14017253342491));
#634=CARTESIAN_POINT('',(13.9283413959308,91.8666365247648,0.912378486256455));
#635=CARTESIAN_POINT('',(13.950733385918,91.8666025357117,0.456248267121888));
#636=CARTESIAN_POINT('',(13.956330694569,91.8665937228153,0.227912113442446));
#637=CARTESIAN_POINT('',(13.9563149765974,91.8665933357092,-0.228758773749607));
#638=CARTESIAN_POINT('',(13.9507020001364,91.8666017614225,-0.457093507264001));
#639=CARTESIAN_POINT('',(13.9282804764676,91.8666325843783,-0.913218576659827));
#640=CARTESIAN_POINT('',(13.9114716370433,91.8666549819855,-1.14100889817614));
#641=CARTESIAN_POINT('',(13.8666991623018,91.8667080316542,-1.5955004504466));
#642=CARTESIAN_POINT('',(13.8387350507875,91.8667386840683,-1.8222016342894));
#643=CARTESIAN_POINT('',(13.7717173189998,91.8668039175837,-2.27396620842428));
#644=CARTESIAN_POINT('',(13.7326633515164,91.8668384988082,-2.49902954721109));
#645=CARTESIAN_POINT('',(13.6435545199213,91.8669108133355,-2.94697454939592));
#646=CARTESIAN_POINT('',(13.5934993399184,91.8669485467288,-3.16985614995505));
#647=CARTESIAN_POINT('',(13.4825082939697,91.8670178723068,-3.61290853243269));
#648=CARTESIAN_POINT('',(13.4215717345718,91.8670494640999,-3.83307914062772));
#649=CARTESIAN_POINT('',(13.2889655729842,91.8670985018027,-4.27017719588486));
#650=CARTESIAN_POINT('',(13.2172953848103,91.8671159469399,-4.48710446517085));
#651=CARTESIAN_POINT('',(13.0633965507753,91.8671327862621,-4.91718421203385));
#652=CARTESIAN_POINT('',(12.9811677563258,91.867132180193,-5.13033663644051));
#653=CARTESIAN_POINT('',(12.8063520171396,91.8671140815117,-5.55234250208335));
#654=CARTESIAN_POINT('',(12.7137654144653,91.8670965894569,-5.76119608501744));
#655=CARTESIAN_POINT('',(12.5184588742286,91.8670494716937,-6.17409426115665));
#656=CARTESIAN_POINT('',(12.4157395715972,91.8670198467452,-6.37813915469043));
#657=CARTESIAN_POINT('',(12.2004161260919,91.8669524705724,-6.78093104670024));
#658=CARTESIAN_POINT('',(12.0878125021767,91.8669147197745,-6.97967832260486));
#659=CARTESIAN_POINT('',(11.8529939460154,91.8668298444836,-7.37140717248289));
#660=CARTESIAN_POINT('',(11.7307791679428,91.8667827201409,-7.56438883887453));
#661=CARTESIAN_POINT('',(11.4770295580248,91.8666916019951,-7.94411830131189));
#662=CARTESIAN_POINT('',(11.345494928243,91.8666476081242,-8.13086623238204));
#663=CARTESIAN_POINT('',(11.0734220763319,91.8665702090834,-8.49767840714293));
#664=CARTESIAN_POINT('',(10.9328840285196,91.8665368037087,-8.67774278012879));
#665=CARTESIAN_POINT('',(10.6431424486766,91.8664841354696,-9.03075759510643));
#666=CARTESIAN_POINT('',(10.493938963,91.8664648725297,-9.20370807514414));
#667=CARTESIAN_POINT('',(10.1872253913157,91.8664407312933,-9.5420828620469));
#668=CARTESIAN_POINT('',(10.0297152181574,91.8664358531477,-9.70750708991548));
#669=CARTESIAN_POINT('',(9.70676674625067,91.8664394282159,-10.0304333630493));
#670=CARTESIAN_POINT('',(9.54132828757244,91.8664478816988,-10.1879352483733));
#671=CARTESIAN_POINT('',(9.20292034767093,91.8664781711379,-10.4946356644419));
#672=CARTESIAN_POINT('',(9.02995073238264,91.8665000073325,-10.6438340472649));
#673=CARTESIAN_POINT('',(8.67689536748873,91.8665629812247,-10.9335579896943));
#674=CARTESIAN_POINT('',(8.49680964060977,91.8666041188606,-11.0740835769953));
#675=CARTESIAN_POINT('',(8.12996776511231,91.8666898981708,-11.3461253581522));
#676=CARTESIAN_POINT('',(7.94321186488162,91.8667345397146,-11.4776418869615));
#677=CARTESIAN_POINT('',(7.56348208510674,91.8668190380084,-11.7313506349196));
#678=CARTESIAN_POINT('',(7.37050847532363,91.8668588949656,-11.8535432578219));
#679=CARTESIAN_POINT('',(6.97880355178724,91.8669303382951,-12.0883119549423));
#680=CARTESIAN_POINT('',(6.78007236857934,91.8669619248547,-12.2008882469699));
#681=CARTESIAN_POINT('',(6.37732345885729,91.8670151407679,-12.4161551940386));
#682=CARTESIAN_POINT('',(6.17330567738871,91.867036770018,-12.5188457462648));
#683=CARTESIAN_POINT('',(5.76046863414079,91.8670683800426,-12.7140954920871));
#684=CARTESIAN_POINT('',(5.55164918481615,91.8670783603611,-12.8066542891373));
#685=CARTESIAN_POINT('',(5.12971071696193,91.8670846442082,-12.9814179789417));
#686=CARTESIAN_POINT('',(4.91659150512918,91.8670809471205,-13.0636224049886));
#687=CARTESIAN_POINT('',(4.48657468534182,91.8670561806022,-13.217479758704));
#688=CARTESIAN_POINT('',(4.26967702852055,91.8670351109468,-13.2891325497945));
#689=CARTESIAN_POINT('',(3.83263152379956,91.8669848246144,-13.4217070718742));
#690=CARTESIAN_POINT('',(3.61248374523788,91.866955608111,-13.4826290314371));
#691=CARTESIAN_POINT('',(3.16946873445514,91.8668969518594,-13.593593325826));
#692=CARTESIAN_POINT('',(2.94660156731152,91.8668675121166,-13.643635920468));
#693=CARTESIAN_POINT('',(2.4986820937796,91.8668118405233,-13.7327239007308));
#694=CARTESIAN_POINT('',(2.27362980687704,91.8667856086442,-13.7717693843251));
#695=CARTESIAN_POINT('',(1.82187850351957,91.8667377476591,-13.8387734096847));
#696=CARTESIAN_POINT('',(1.59517947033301,91.8667161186,-13.8667318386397));
#697=CARTESIAN_POINT('',(1.14067777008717,91.8666782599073,-13.9114954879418));
#698=CARTESIAN_POINT('',(0.91287507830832,91.8666620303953,-13.9283004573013));
#699=CARTESIAN_POINT('',(0.456715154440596,91.8666410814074,-13.9507179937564));
#700=CARTESIAN_POINT('',(0.228357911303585,91.8666363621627,-13.956330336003));
#701=CARTESIAN_POINT('',(0.,91.8666404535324,-13.9563269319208));
#702=B_SPLINE_CURVE_WITH_KNOTS('',3,(#444,#445,#446,#447,#448,#449,#450,#451,#452,#453,#454,
#455,#456,#457,#458,#459,#460,#461,#462,#463,#464,#465,#466,#467,#468,#469,#470,#471,#472,#473,
#474,#475,#476,#477,#478,#479,#480,#481,#482,#483,#484,#485,#486,#487,#488,#489,#490,#491,#492,
#493,#494,#495,#496,#497,#498,#499,#500,#501,#502,#503,#504,#505,#506,#507,#508,#509,#510,#511,
#512,#513,#514,#515,#516,#517,#518,#519,#520,#521,#522,#523,#524,#525,#526,#527,#528,#529,#530,
#531,#532,#533,#534,#535,#536,#537,#538,#539,#540,#541,#542,#543,#544,#545,#546,#547,#548,#549,
#550,#551,#552,#553,#554,#555,#556,#557,#558,#559,#560,#561,#562,#563,#564,#565,#566,#567,#568,
#569,#570,#571,#572,#573,#574,#575,#576,#577,#578,#579,#580,#581,#582,#583,#584,#585,#586,#587,
#588,#589,#590,#591,#592,#593,#594,#595,#596,#597,#598,#599,#600,#601,#602,#603,#604,#605,#606,
#607,#608,#609,#610,#611,#612,#613,#614,#615,#616,#617,#618,#619,#620,#621,#622,#623,#624,#625,
#626,#627,#628,#629,#630,#631,#632,#633,#634,#635,#636,#637,#638,#639,#640,#641,#642,#643,#644,
#645,#646,#647,#648,#649,#650,#651,#652,#653,#654,#655,#656,#657,#658,#659,#660,#661,#662,#663,
#664,#665,#666,#667,#668,#669,#670,#671,#672,#673,#674,#675,#676,#677,#678,#679,#680,#681,#682,
#683,#684,#685,#686,#687,#688,#689,#690,#691,#692,#693,#694,#695,#696,#697,#698,#699,#700,#701),
.UNSPECIFIED.,.F.,.F.,(4,2,2,2,2,2,2,2,2,2,2,2,2,2,2,2,2,2,2,2,2,2,2,2,2,2,2,2,2,2,2,2,2,2,2,2,
2,2,2,2,2,2,2,2,2,2,2,2,2,2,2,2,2,2,2,2,2,2,2,2,2,2,2,2,2,2,2,2,2,2,2,2,2,2,2,2,2,2,2,2,2,2,2,2,
2,2,2,2,2,2,2,2,2,2,2,2,2,2,2,2,2,2,2,2,2,2,2,2,2,2,2,2,2,2,2,2,2,2,2,2,2,2,2,2,2,2,2,2,4),(0.,
0.685003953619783,1.36999411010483,2.05496869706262,2.73993617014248,3.42490969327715,
4.10989964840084,4.79490437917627,5.47990043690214,6.16486569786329,6.84980411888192,
7.53473531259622,8.21968190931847,8.90465811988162,9.58965986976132,10.2746639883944,
10.9596560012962,11.6446341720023,12.3296050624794,13.0145794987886,13.6995671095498,
14.384569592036,15.0695832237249,15.7546328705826,16.4397253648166,17.1248403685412,
17.8099456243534,18.4950134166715,19.1800375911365,19.8650422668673,20.5500255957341,
21.2349796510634,21.9199157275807,22.6048547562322,23.2898165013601,23.9748081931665,
24.6598185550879,25.3448791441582,26.0300191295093,26.7152125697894,27.4004047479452,
28.0855415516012,28.7705988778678,29.4556083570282,30.1405991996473,30.8255601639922,
31.5104989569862,32.1954354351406,32.8803903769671,33.5653746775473,34.2503798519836,
34.9354092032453,35.6204910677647,36.3056167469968,36.9907526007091,37.6758601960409,
38.3609160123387,39.0459298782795,39.7309268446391,40.4158927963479,41.1008307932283,
41.7857604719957,42.4707049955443,43.1556793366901,43.8406802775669,44.5256813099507,
45.210655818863,45.8956004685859,46.5805301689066,47.2654680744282,47.9504338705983,
48.6354307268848,49.3204446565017,50.0055006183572,50.6906083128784,51.375744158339,
52.0608697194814,52.7459514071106,53.4309806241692,54.1159858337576,54.800970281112,
55.4859253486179,56.1708618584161,56.8558005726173,57.5407613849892,58.2257520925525,
58.9107615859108,59.595819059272,60.2809560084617,60.9661482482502,61.6513416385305,
62.3364814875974,63.0215419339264,63.7065522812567,64.3915441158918,65.0765060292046,
65.7614451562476,66.4463812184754,67.1313351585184,67.8163183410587,68.5013229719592,
69.1863472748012,69.8714152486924,70.5565206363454,71.2416356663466,71.9267280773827,
72.6117775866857,73.2967911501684,73.9817937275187,74.6667814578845,75.3517559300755,
76.0367267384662,76.7217047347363,77.4066965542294,78.091700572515,78.7767024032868,
79.4616787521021,80.1466254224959,80.831556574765,81.5164948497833,82.2014599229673,
82.886455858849,83.571460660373,84.2564508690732,84.9414247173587,85.6263924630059,
86.3113671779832,86.9963573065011,87.681361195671),.UNSPECIFIED.);
#703=CARTESIAN_POINT('',(0.,91.8666404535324,-13.9563269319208));
#704=VERTEX_POINT('',#703);
#705=EDGE_CURVE('E84',#704,#704,#702,.F.);
#706=ORIENTED_EDGE('',*,*,#705,.F.);
#707=EDGE_LOOP('',(#706));
#708=FACE_BOUND('',#707,.T.);
#709=ADVANCED_FACE('F146',(#708),#443,.T.);
#710=OPEN_SHELL('',(#709));
#711=SHELL_BASED_SURFACE_MODEL('B38',(#710));
#712=ADVANCED_BREP_SHAPE_REPRESENTATION('',(#18,#406),#14);
#713=MANIFOLD_SURFACE_SHAPE_REPRESENTATION('',(#18,#324,#711),#14);
#714=SHAPE_REPRESENTATION('',(#18),#14);
#715=SHAPE_DEFINITION_REPRESENTATION(#9,#714);
#716=SHAPE_REPRESENTATION_RELATIONSHIP('','',#714,#712);
#717=SHAPE_REPRESENTATION_RELATIONSHIP('','',#714,#713);
ENDSEC;
END-ISO-10303-21;
